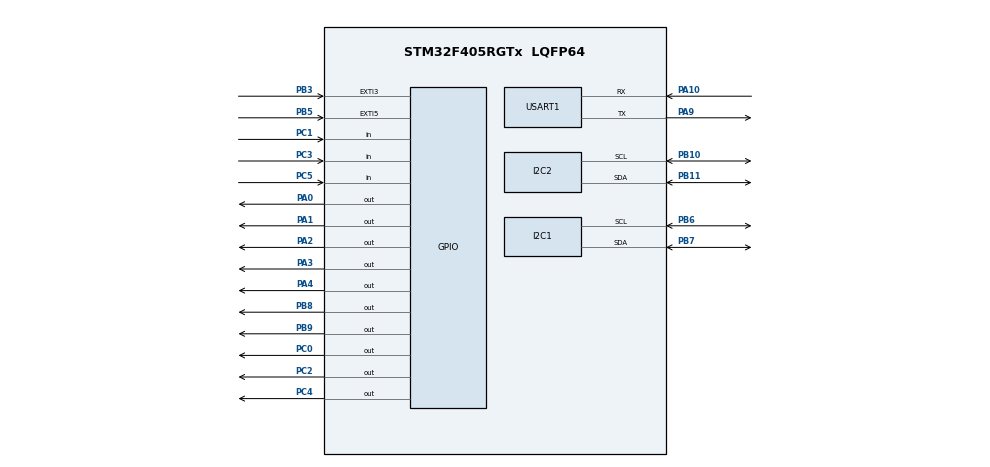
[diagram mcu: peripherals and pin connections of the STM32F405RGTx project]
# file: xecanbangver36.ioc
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Mcu.Family=STM32F4
Mcu.Name=STM32F405RGTx
Mcu.Package=LQFP64
NVIC.PriorityGroup=NVIC_PRIORITYGROUP_4
PA0-WKUP.PinState=GPIO_PIN_SET
PA0-WKUP.Signal=GPIO_Output
PA1.Signal=GPIO_Output
PA13.Mode=Serial_Wire
PA13.Signal=SYS_JTMS-SWDIO
PA14.Mode=Serial_Wire
PA14.Signal=SYS_JTCK-SWCLK
PA9.Mode=Asynchronous
PA9.Signal=USART1_TX
PA10.Mode=Asynchronous
PA10.Signal=USART1_RX
PA2.Signal=GPIO_Output
PA3.Signal=GPIO_Output
PA4.Signal=GPIO_Output
PB10.Mode=I2C
PB10.Signal=I2C2_SCL
PB11.Mode=I2C
PB11.Signal=I2C2_SDA
PB13.Signal=SPI2_SCK
PB14.Signal=SPI2_MISO
PB15.Signal=SPI2_MOSI
PB3.Signal=GPXTI3
PB5.Signal=GPXTI5
PB6.Mode=I2C
PB6.Signal=I2C1_SCL
PB7.Mode=I2C
PB7.Signal=I2C1_SDA
PB8.Signal=GPIO_Output
PB9.PinState=GPIO_PIN_SET
PB9.Signal=GPIO_Output
PC0.Signal=GPIO_Output
PC1.Signal=GPIO_Input
PC14-OSC32_IN.Mode=LSE-External-Oscillator
PC14-OSC32_IN.Signal=RCC_OSC32_IN
PC15-OSC32_OUT.Mode=LSE-External-Oscillator
PC15-OSC32_OUT.Signal=RCC_OSC32_OUT
PC2.Signal=GPIO_Output
PC3.Signal=GPIO_Input
PC4.Signal=GPIO_Output
PC5.Signal=GPIO_Input
PH0-OSC_IN.Mode=HSE-External-Oscillator
PH0-OSC_IN.Signal=RCC_OSC_IN
PH1-OSC_OUT.Mode=HSE-External-Oscillator
PH1-OSC_OUT.Signal=RCC_OSC_OUT
ProjectManager.HeapSize=0x200
ProjectManager.StackSize=0x400
ProjectManager.TargetToolchain=CMake
RCC.48MHZClocksFreq_Value=48000000
RCC.AHBCLKDivider=RCC_SYSCLK_DIV2
RCC.AHBFreq_Value=48000000
RCC.APB1CLKDivider=RCC_HCLK_DIV2
RCC.APB1Freq_Value=24000000
RCC.APB1TimFreq_Value=48000000
RCC.APB2Freq_Value=48000000
RCC.APB2TimFreq_Value=48000000
RCC.CortexFreq_Value=48000000
RCC.HCLKFreq_Value=48000000
RCC.HSE_VALUE=8000000
RCC.HSI_VALUE=16000000
RCC.PLLM=8
RCC.PLLN=96
RCC.SYSCLKFreq_VALUE=96000000
RCC.SYSCLKSource=RCC_SYSCLKSOURCE_PLLCLK
RCC.VCOOutputFreq_Value=192000000
board=custom

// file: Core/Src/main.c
/* USER CODE BEGIN Header */
/**
  ******************************************************************************
  * @file           : main.c
  * @brief          : Main program body
  ******************************************************************************
  * @attention
  *
  * Copyright (c) 2026 STMicroelectronics.
  * All rights reserved.
  *
  * This software is licensed under terms that can be found in the LICENSE file
  * in the root directory of this software component.
  * If no LICENSE file comes with this software, it is provided AS-IS.
  *
  ******************************************************************************
  */
/* USER CODE END Header */
#include "main.h"

/* USER CODE BEGIN Includes */
#include "app.h"
/* USER CODE END Includes */

I2C_HandleTypeDef hi2c1;
I2C_HandleTypeDef hi2c2;

void SystemClock_Config(void);
static void MX_GPIO_Init(void);
static void MX_I2C1_Init(void);
static void MX_I2C2_Init(void);

int main(void)
{

  /* MCU Configuration--------------------------------------------------------*/

  /* Reset of all peripherals, Initializes the Flash interface and the Systick. */
  HAL_Init();

  /* USER CODE BEGIN Init */
  /* Quy tắc an toàn 1 (AGENTS.md): Driver phải TẮT ngay khi boot (PA0 active-low = HIGH) */
  __HAL_RCC_GPIOA_CLK_ENABLE();
  GPIO_InitTypeDef init_pa0 = {0};
  init_pa0.Pin = GPIO_PIN_0;
  init_pa0.Mode = GPIO_MODE_OUTPUT_PP;
  init_pa0.Pull = GPIO_PULLUP;
  init_pa0.Speed = GPIO_SPEED_FREQ_LOW;
  HAL_GPIO_Init(GPIOA, &init_pa0);
  HAL_GPIO_WritePin(GPIOA, GPIO_PIN_0, GPIO_PIN_SET);
  /* USER CODE END Init */

  /* Configure the system clock */
  SystemClock_Config();

  /* Initialize all configured peripherals */
  MX_GPIO_Init();
  MX_I2C1_Init();
  MX_I2C2_Init();
  /* USER CODE BEGIN 2 */
  app_init();
  /* USER CODE END 2 */

  /* Infinite loop */
  /* USER CODE BEGIN WHILE */
  while (1)
  {
    app_loop();
    /* USER CODE END WHILE */

  }
}

void SystemClock_Config(void)
{
  RCC_OscInitTypeDef RCC_OscInitStruct = {0};
  RCC_ClkInitTypeDef RCC_ClkInitStruct = {0};

  /** Configure the main internal regulator output voltage
  */
  __HAL_RCC_PWR_CLK_ENABLE();
  __HAL_PWR_VOLTAGESCALING_CONFIG(PWR_REGULATOR_VOLTAGE_SCALE1);

  /** Initializes the RCC Oscillators according to the specified parameters
  * in the RCC_OscInitTypeDef structure: 8 MHz HSE crystal -> 168 MHz SYSCLK.
  */
  RCC_OscInitStruct.OscillatorType = RCC_OSCILLATORTYPE_HSE;
  RCC_OscInitStruct.HSEState = RCC_HSE_ON;
  RCC_OscInitStruct.PLL.PLLState = RCC_PLL_ON;
  RCC_OscInitStruct.PLL.PLLSource = RCC_PLLSOURCE_HSE;
  RCC_OscInitStruct.PLL.PLLM = 8;
  RCC_OscInitStruct.PLL.PLLN = 336;
  RCC_OscInitStruct.PLL.PLLP = RCC_PLLP_DIV2;
  RCC_OscInitStruct.PLL.PLLQ = 7;
  if (HAL_RCC_OscConfig(&RCC_OscInitStruct) != HAL_OK)
  {
    Error_Handler();
  }

  /** Initializes the CPU, AHB and APB buses clocks
  */
  RCC_ClkInitStruct.ClockType = RCC_CLOCKTYPE_HCLK|RCC_CLOCKTYPE_SYSCLK
                              |RCC_CLOCKTYPE_PCLK1|RCC_CLOCKTYPE_PCLK2;
  RCC_ClkInitStruct.SYSCLKSource = RCC_SYSCLKSOURCE_PLLCLK;
  RCC_ClkInitStruct.AHBCLKDivider = RCC_SYSCLK_DIV1;
  RCC_ClkInitStruct.APB1CLKDivider = RCC_HCLK_DIV4;
  RCC_ClkInitStruct.APB2CLKDivider = RCC_HCLK_DIV2;

  if (HAL_RCC_ClockConfig(&RCC_ClkInitStruct, FLASH_LATENCY_5) != HAL_OK)
  {
    Error_Handler();
  }
}

static void MX_I2C1_Init(void)
{

  hi2c1.Instance = I2C1;
  hi2c1.Init.ClockSpeed = 400000;
  hi2c1.Init.DutyCycle = I2C_DUTYCYCLE_2;
  hi2c1.Init.OwnAddress1 = 0;
  hi2c1.Init.AddressingMode = I2C_ADDRESSINGMODE_7BIT;
  hi2c1.Init.DualAddressMode = I2C_DUALADDRESS_DISABLE;
  hi2c1.Init.OwnAddress2 = 0;
  hi2c1.Init.GeneralCallMode = I2C_GENERALCALL_DISABLE;
  hi2c1.Init.NoStretchMode = I2C_NOSTRETCH_DISABLE;
  if (HAL_I2C_Init(&hi2c1) != HAL_OK)
  {
    Error_Handler();
  }

}

static void MX_I2C2_Init(void)
{

  hi2c2.Instance = I2C2;
  hi2c2.Init.ClockSpeed = 100000;
  hi2c2.Init.DutyCycle = I2C_DUTYCYCLE_2;
  hi2c2.Init.OwnAddress1 = 0;
  hi2c2.Init.AddressingMode = I2C_ADDRESSINGMODE_7BIT;
  hi2c2.Init.DualAddressMode = I2C_DUALADDRESS_DISABLE;
  hi2c2.Init.OwnAddress2 = 0;
  hi2c2.Init.GeneralCallMode = I2C_GENERALCALL_DISABLE;
  hi2c2.Init.NoStretchMode = I2C_NOSTRETCH_DISABLE;
  if (HAL_I2C_Init(&hi2c2) != HAL_OK)
  {
    Error_Handler();
  }

}

static void MX_GPIO_Init(void)
{
  GPIO_InitTypeDef GPIO_InitStruct = {0};

  /* GPIO Ports Clock Enable */
  __HAL_RCC_GPIOC_CLK_ENABLE();
  __HAL_RCC_GPIOH_CLK_ENABLE();
  __HAL_RCC_GPIOA_CLK_ENABLE();
  __HAL_RCC_GPIOB_CLK_ENABLE();

  /*Configure GPIO pin Output Level */
  HAL_GPIO_WritePin(GPIOC, GPIO_PIN_0|GPIO_PIN_2|GPIO_PIN_4, GPIO_PIN_RESET);

  /*Configure GPIO pin Output Level: TMC2208 EN (PA0) must be HIGH (disabled) at boot */
  HAL_GPIO_WritePin(GPIOA, GPIO_PIN_1|GPIO_PIN_2|GPIO_PIN_3|GPIO_PIN_4, GPIO_PIN_RESET);
  HAL_GPIO_WritePin(GPIOA, GPIO_PIN_0, GPIO_PIN_SET);

  /*Configure GPIO pin Output Level: NRF24 CE (PB8) low, CSN (PB9) high */
  HAL_GPIO_WritePin(GPIOB, GPIO_PIN_8, GPIO_PIN_RESET);
  HAL_GPIO_WritePin(GPIOB, GPIO_PIN_9, GPIO_PIN_SET);

  /*Configure GPIO pins : PC0 PC2 PC4 (HC-SR05 TRIG - OUTPUT) */
  GPIO_InitStruct.Pin = GPIO_PIN_0|GPIO_PIN_2|GPIO_PIN_4;
  GPIO_InitStruct.Mode = GPIO_MODE_OUTPUT_PP;
  GPIO_InitStruct.Pull = GPIO_NOPULL;
  GPIO_InitStruct.Speed = GPIO_SPEED_FREQ_LOW;
  HAL_GPIO_Init(GPIOC, &GPIO_InitStruct);

  /*Configure GPIO pins : PC1 PC3 PC5 (HC-SR05 ECHO - INPUT) */
  GPIO_InitStruct.Pin = GPIO_PIN_1|GPIO_PIN_3|GPIO_PIN_5;
  GPIO_InitStruct.Mode = GPIO_MODE_INPUT;
  GPIO_InitStruct.Pull = GPIO_NOPULL;
  HAL_GPIO_Init(GPIOC, &GPIO_InitStruct);

  /*Configure GPIO pins : PA0 PA1 PA2 PA3
                           PA4 */
  GPIO_InitStruct.Pin = GPIO_PIN_0|GPIO_PIN_1|GPIO_PIN_2|GPIO_PIN_3
                          |GPIO_PIN_4;
  GPIO_InitStruct.Mode = GPIO_MODE_OUTPUT_PP;
  GPIO_InitStruct.Pull = GPIO_NOPULL;
  GPIO_InitStruct.Speed = GPIO_SPEED_FREQ_LOW;
  HAL_GPIO_Init(GPIOA, &GPIO_InitStruct);

  /*Configure GPIO pins : PB13 PB14 PB15 */
  GPIO_InitStruct.Pin = GPIO_PIN_13|GPIO_PIN_14|GPIO_PIN_15;
  GPIO_InitStruct.Mode = GPIO_MODE_AF_PP;
  GPIO_InitStruct.Pull = GPIO_NOPULL;
  GPIO_InitStruct.Speed = GPIO_SPEED_FREQ_VERY_HIGH;
  GPIO_InitStruct.Alternate = GPIO_AF5_SPI2;
  HAL_GPIO_Init(GPIOB, &GPIO_InitStruct);

  /*Configure GPIO pins : PB3 PB5 */
  GPIO_InitStruct.Pin = GPIO_PIN_3|GPIO_PIN_5;
  GPIO_InitStruct.Mode = GPIO_MODE_IT_RISING;
  GPIO_InitStruct.Pull = GPIO_NOPULL;
  HAL_GPIO_Init(GPIOB, &GPIO_InitStruct);

  /*Configure GPIO pins : PB8 PB9 */
  GPIO_InitStruct.Pin = GPIO_PIN_8|GPIO_PIN_9;
  GPIO_InitStruct.Mode = GPIO_MODE_OUTPUT_PP;
  GPIO_InitStruct.Pull = GPIO_NOPULL;
  GPIO_InitStruct.Speed = GPIO_SPEED_FREQ_LOW;
  HAL_GPIO_Init(GPIOB, &GPIO_InitStruct);

  /* USER CODE BEGIN MX_GPIO_Init_2 */
  /* Enable EXTI3 for MPU6050 INT (PB3) */
  HAL_NVIC_SetPriority(EXTI3_IRQn, 5, 0);
  HAL_NVIC_EnableIRQ(EXTI3_IRQn);
  /* USER CODE END MX_GPIO_Init_2 */
}

void Error_Handler(void)
{
  __disable_irq();
  while (1)
  {
  }
}
